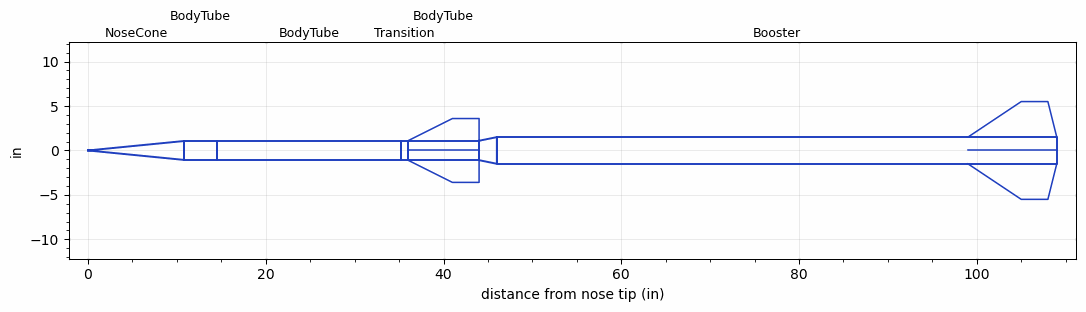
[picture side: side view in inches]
<RASAeroDocument>
 <FileVersion>2</FileVersion>
 <RocketDesign>
  <NoseCone>
   <Length>10.8</Length>
   <Diameter>2.125</Diameter>
   <Shape>Conical</Shape>
   <BluntRadius>0.02</BluntRadius>
   <Location>0</Location>
  </NoseCone>
  <BodyTube>
   <Length>3.7</Length>
   <Diameter>2.125</Diameter>
   <Location>10.8</Location>
  </BodyTube>
  <BodyTube>
   <Length>20.75</Length>
   <Diameter>2.125</Diameter>
   <Location>14.5</Location>
  </BodyTube>
  <Transition>
   <Length>0.75</Length>
   <Diameter>2.185</Diameter>
   <Location>35.25</Location>
   <RearDiameter>2.185</RearDiameter>
  </Transition>
  <BodyTube>
   <Length>8</Length>
   <Diameter>2.185</Diameter>
   <Location>36</Location>
   <Fin>
    <Count>4</Count>
    <Chord>8</Chord>
    <Span>2.5</Span>
    <SweepDistance>5</SweepDistance>
    <TipChord>3</TipChord>
    <Thickness>0.125</Thickness>
    <LERadius>0.02</LERadius>
    <Location>8</Location>
    <AirfoilSection>Double Wedge</AirfoilSection>
    <FX1>1.5</FX1>
   </Fin>
  </BodyTube>
  <Booster>
   <Length>63</Length>
   <Diameter>3</Diameter>
   <InsideDiameter>2.185</InsideDiameter>
   <Location>44</Location>
   <ShoulderLength>2</ShoulderLength>
   <Fin>
    <Count>4</Count>
    <Chord>10</Chord>
    <Span>4</Span>
    <SweepDistance>6</SweepDistance>
    <TipChord>3</TipChord>
    <Thickness>0.1875</Thickness>
    <LERadius>0.02</LERadius>
    <Location>10</Location>
    <AirfoilSection>Double Wedge</AirfoilSection>
    <FX1>1.5</FX1>
   </Fin>
  </Booster>
  <Surface>Rough Camouflage Paint</Surface>
  <ModifiedBarrowman>True</ModifiedBarrowman>
  <Turbulence>True</Turbulence>
  <UseBooster1>True</UseBooster1>
  <UseBooster2>False</UseBooster2>
 </RocketDesign>
 <LaunchSite>
  <Altitude>3900</Altitude>
  <Pressure>0</Pressure>
  <RodAngle>1</RodAngle>
  <RodLength>10</RodLength>
  <Temperature>80</Temperature>
  <WindSpeed>4.47</WindSpeed>
 </LaunchSite>
 <Recovery>
  <Altitude1>3000</Altitude1>
  <Altitude2>3000</Altitude2>
  <DeviceType1>Parachute</DeviceType1>
  <DeviceType2>Parachute</DeviceType2>
  <Event1>True</Event1>
  <Event2>True</Event2>
  <Size1>4</Size1>
  <Size2>35.9999</Size2>
  <EventType1>Apogee</EventType1>
  <EventType2>Altitude</EventType2>
  <CD1>2.2</CD1>
  <CD2>0</CD2>
 </Recovery>
 <SimulationList>
  <Simulation>
   <SustainerEngine>L1081  (boostkareilley)</SustainerEngine>
   <SustainerLaunchWt>8</SustainerLaunchWt>
   <SustainerNozzleDiameter>1.9</SustainerNozzleDiameter>
   <SustainerCG>29.3</SustainerCG>
   <SustainerIgnitionDelay>14</SustainerIgnitionDelay>
   <Booster1Engine>N3262BPF  (Polaris)</Booster1Engine>
   <Booster1LaunchWt>32</Booster1LaunchWt>
   <Booster1SeparationDelay>0</Booster1SeparationDelay>
   <Booster1IgnitionDelay>0</Booster1IgnitionDelay>
   <Booster1CG>60.9</Booster1CG>
   <Booster1NozzleDiameter>3</Booster1NozzleDiameter>
   <IncludeBooster1>True</IncludeBooster1>
   <Booster2Delay>0</Booster2Delay>
   <IncludeBooster2>False</IncludeBooster2>
   <TimetoApogee>117.2259</TimetoApogee>
   <MaxAltitude>192527.3</MaxAltitude>
   <MaxVelocity>4613.965</MaxVelocity>
  </Simulation>
  <Simulation>
   <SustainerLaunchWt>4.1888</SustainerLaunchWt>
   <SustainerCG>29.2999</SustainerCG>
   <SustainerIgnitionDelay>0</SustainerIgnitionDelay>
   <Booster1LaunchWt>7.8756</Booster1LaunchWt>
   <Booster1SeparationDelay>0</Booster1SeparationDelay>
   <Booster1IgnitionDelay>0</Booster1IgnitionDelay>
   <Booster1CG>47.5404</Booster1CG>
   <IncludeBooster1>True</IncludeBooster1>
   <Booster2Delay>0</Booster2Delay>
   <IncludeBooster2>False</IncludeBooster2>
  </Simulation>
  <Simulation>
   <SustainerLaunchWt>7.6072</SustainerLaunchWt>
   <SustainerCG>29.4437</SustainerCG>
   <SustainerIgnitionDelay>10</SustainerIgnitionDelay>
   <Booster1LaunchWt>31.0965</Booster1LaunchWt>
   <Booster1SeparationDelay>0</Booster1SeparationDelay>
   <Booster1IgnitionDelay>0</Booster1IgnitionDelay>
   <Booster1CG>63.345</Booster1CG>
   <IncludeBooster1>True</IncludeBooster1>
   <Booster2Delay>0</Booster2Delay>
   <IncludeBooster2>False</IncludeBooster2>
  </Simulation>
 </SimulationList>
</RASAeroDocument>
